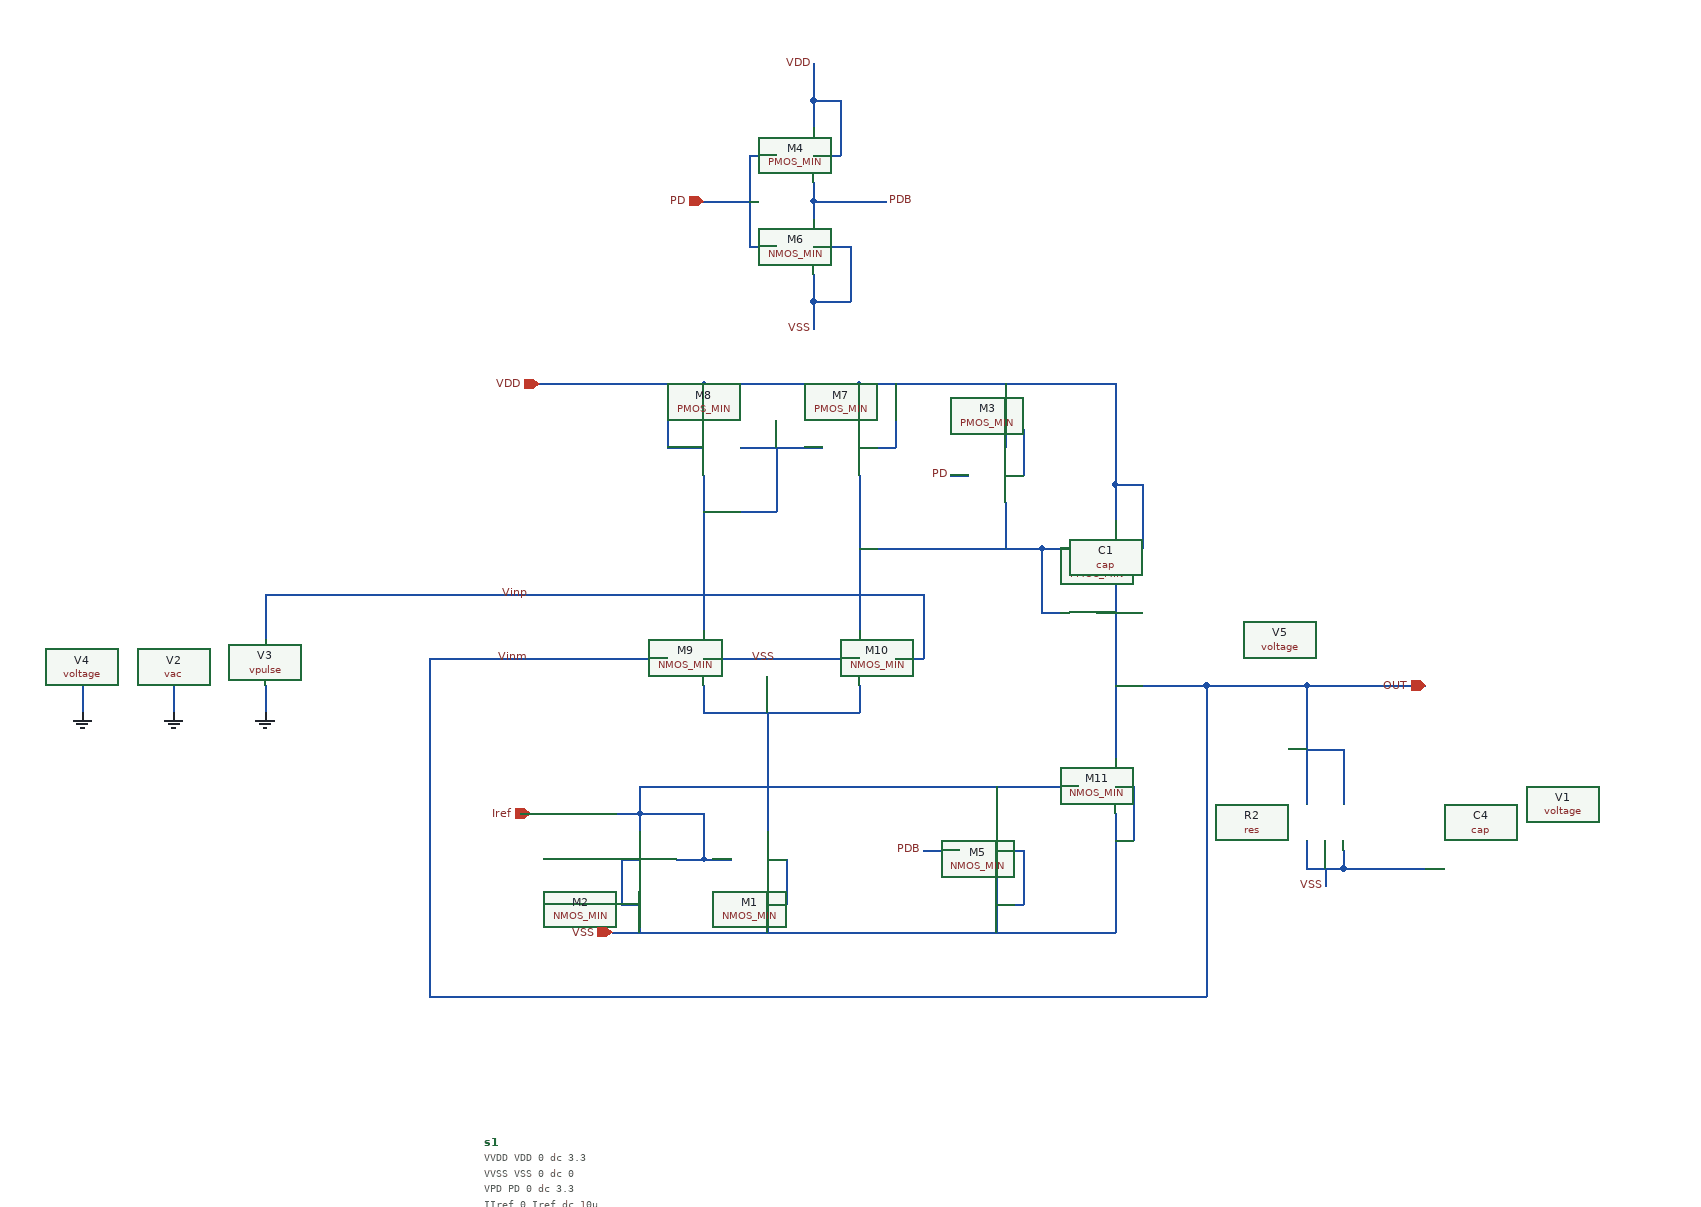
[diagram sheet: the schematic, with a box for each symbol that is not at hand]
v {xschem version=3.4.8RC file_version=1.3}
G {}
K {}
V {}
S {}
F {}
E {}
N 270 160 300 160 {lab=VDD}
N -360 -20 -180 -20 {lab=VDD}
N -180 -20 -180 20 {lab=VDD}
N -180 -20 -10 -20 {lab=VDD}
N -10 -20 -10 20 {lab=VDD}
N -10 -20 170 -20 {lab=VDD}
N 270 -20 270 90 {lab=VDD}
N 300 90 300 160 {lab=VDD}
N 270 90 300 90 {lab=VDD}
N -10 50 30 50 {lab=VDD}
N 30 -20 30 50 {lab=VDD}
N -220 50 -180 50 {lab=VDD}
N -220 -20 -220 50 {lab=VDD}
N -100 50 -100 100 {lab=#net1}
N -180 120 -100 120 {lab=#net1}
N -360 210 60 210 {lab=Vinp}
N 60 210 60 280 {lab=Vinp}
N 30 280 60 280 {lab=Vinp}
N -180 310 -180 340 {lab=#net2}
N -180 340 -10 340 {lab=#net2}
N -10 310 -10 340 {lab=#net2}
N -180 280 -10 280 {lab=VSS}
N -140 50 -50 50 {lab=#net1}
N -60 580 170 580 {lab=VSS}
N -300 280 -220 280 {lab=OUT}
N -320 280 -300 280 {lab=OUT}
N -110 530 -110 580 {lab=VSS}
N -110 500 -90 500 {lab=VSS}
N -90 500 -90 550 {lab=VSS}
N -110 550 -90 550 {lab=VSS}
N -280 580 -60 580 {lab=VSS}
N -180 500 -150 500 {lab=Iref}
N -210 500 -180 500 {lab=Iref}
N -250 530 -250 580 {lab=VSS}
N -270 500 -250 500 {lab=VSS}
N -270 500 -270 550 {lab=VSS}
N -270 550 -250 550 {lab=VSS}
N -10 160 50 160 {lab=#net3}
N -180 450 -180 500 {lab=Iref}
N -250 450 -180 450 {lab=Iref}
N -380 450 -250 450 {lab=Iref}
N -250 450 -250 470 {lab=Iref}
N -250 420 -250 450 {lab=Iref}
N 270 190 270 220 {lab=OUT}
N 230 -20 270 -20 {lab=VDD}
N 190 160 230 160 {lab=#net3}
N 190 160 190 230 {lab=#net3}
N 270 450 270 580 {lab=VSS}
N 230 580 270 580 {lab=VSS}
N 270 420 290 420 {lab=VSS}
N 290 420 290 480 {lab=VSS}
N 270 480 290 480 {lab=VSS}
N -480 650 280 650 {lab=OUT}
N -480 280 -480 650 {lab=OUT}
N -480 280 -320 280 {lab=OUT}
N -110 380 -110 470 {lab=#net2}
N 370 310 370 640 {lab=OUT}
N 250 230 270 230 {lab=OUT}
N 190 230 210 230 {lab=#net3}
N -110 340 -110 360 {lab=#net2}
N 270 220 270 320 {lab=OUT}
N 50 160 80 160 {lab=#net3}
N 270 320 270 340 {lab=OUT}
N 80 160 130 160 {lab=#net3}
N -180 80 -180 250 {lab=#net1}
N -100 100 -100 120 {lab=#net1}
N -10 80 -10 250 {lab=#net3}
N 270 90 270 120 {lab=VDD}
N 270 120 270 130 {lab=VDD}
N -110 360 -110 380 {lab=#net2}
N -660 210 -660 260 {lab=Vinp}
N -660 210 -360 210 {lab=Vinp}
N 140 520 140 560 {lab=VSS}
N 60 490 100 490 {lab=PDB}
N 140 420 140 450 {lab=Iref}
N 140 490 170 490 {lab=VSS}
N 170 490 170 550 {lab=VSS}
N 140 550 170 550 {lab=VSS}
N 140 450 140 460 {lab=Iref}
N 140 560 140 580 {lab=VSS}
N 150 30 150 50 {lab=VDD}
N 150 80 170 80 {lab=VDD}
N 170 30 170 80 {lab=VDD}
N 150 30 170 30 {lab=VDD}
N 150 120 150 160 {lab=#net3}
N 90 80 110 80 {lab=PD}
N 270 340 270 390 {lab=OUT}
N -250 420 80 420 {lab=Iref}
N 130 160 190 160 {lab=#net3}
N 170 -20 230 -20 {lab=VDD}
N 150 110 150 120 {lab=#net3}
N 150 -20 150 30 {lab=VDD}
N 170 580 230 580 {lab=VSS}
N 80 420 230 420 {lab=Iref}
N -60 -330 -60 -300 {lab=VDD}
N -60 -170 -20 -170 {lab=VSS}
N -20 -170 -20 -110 {lab=VSS}
N -60 -110 -20 -110 {lab=VSS}
N -60 -270 -30 -270 {lab=VDD}
N -30 -330 -30 -270 {lab=VDD}
N -60 -330 -30 -330 {lab=VDD}
N -60 -220 -60 -200 {lab=PDB}
N -60 -140 -60 -110 {lab=VSS}
N -60 -340 -60 -330 {lab=VDD}
N -60 -240 -60 -220 {lab=PDB}
N -60 -110 -60 -80 {lab=VSS}
N -130 -270 -100 -270 {lab=PD}
N -130 -270 -130 -170 {lab=PD}
N -130 -170 -100 -170 {lab=PD}
N -60 -350 -60 -340 {lab=VDD}
N -60 -370 -60 -350 {lab=VDD}
N -180 -220 -130 -220 {lab=PD}
N -60 -220 20 -220 {lab=PDB}
N 280 650 370 650 {lab=OUT}
N 370 640 370 650 {lab=OUT}
N -760 310 -760 340 {lab=GND}
N -660 310 -660 340 {lab=GND}
N -860 310 -860 340 {lab=GND}
N 480 310 540 310 {lab=OUT}
N 480 480 480 510 {lab=VSS}
N 500 510 500 530 {lab=VSS}
N 480 400 480 440 {lab=OUT}
N 480 370 480 400 {lab=OUT}
N 480 380 520 380 {lab=OUT}
N 520 380 520 440 {lab=OUT}
N 520 490 520 510 {lab=VSS}
N 480 510 520 510 {lab=VSS}
N 480 310 480 370 {lab=OUT}
N 540 310 610 310 {lab=OUT}
N 520 510 610 510 {lab=VSS}
N 270 310 370 310 {lab=OUT}
N 370 310 390 310 {lab=OUT}
N 470 310 480 310 {lab=OUT}
N 440 310 470 310 {lab=OUT}
N 390 310 440 310 {lab=OUT}
C {PMOS_MIN.sym} -50 50 0 0 {name=M7 model=p3.0 w=20u l=0.5u as=0 ps=0 ad=0 pd=0 m=1}
C {PMOS_MIN.sym} -140 50 0 1 {name=M8 model=p3.0 w=20u l=0.5u as=0 ps=0 ad=0 pd=0 m=1}
C {NMOS_MIN.sym} -220 280 0 0 {name=M9 model=n3.0 w=20u l=0.5u as=0 ps=0 ad=0 pd=0 m=1}
C {NMOS_MIN.sym} 30 280 0 1 {name=M10 model=n3.0 w=20u l=0.5u as=0 ps=0 ad=0 pd=0 m=1}
C {NMOS_MIN.sym} 230 420 0 0 {name=M11 model=n3.0 w=20u l=0.5u as=0 ps=0 ad=0 pd=0 m=1}
C {PMOS_MIN.sym} 230 160 0 0 {name=M12 model=p3.0 w=40u l=0.5u as=0 ps=0 ad=0 pd=0 m=1}
C {ipin.sym} -360 -20 0 0 {name=p5 lab=VDD}
C {iopin.sym} 610 310 0 0 {name=p7 lab=OUT}
C {ipin.sym} -370 450 0 0 {name=p1 lab=Iref}
C {NMOS_MIN.sym} -150 500 0 0 {name=M1 model=n3.0 w=20u l=0.5u as=0 ps=0 ad=0 pd=0 m=1}
C {NMOS_MIN.sym} -210 500 0 1 {name=M2 model=n3.0 w=20u l=0.5u as=0 ps=0 ad=0 pd=0 m=1}
C {lab_pin.sym} -370 210 1 0 {name=l3 sig_type=std_logic lab=Vinp}
C {lab_pin.sym} -100 280 1 0 {name=l5 sig_type=std_logic lab=VSS}
C {ipin.sym} -280 580 0 0 {name=p2 lab=VSS}
C {cap.sym} 250 220 1 0 {name=C1
m=1
value=1p
footprint=1206
device=ceramic}
C {lab_pin.sym} -370 280 3 0 {name=l8 sig_type=std_logic lab=Vinm}
C {NMOS_MIN.sym} 100 490 0 0 {name=M5 model=n3.0 w=3.5u l=0.35u as=0 ps=0 ad=0 pd=0 m=1}
C {PMOS_MIN.sym} 110 80 0 0 {name=M3 model=p3.0 w=3.5u l=0.35u as=0 ps=0 ad=0 pd=0 m=1}
C {PMOS_MIN.sym} -100 -270 0 0 {name=M4 model=p3.0 w=3.5u l=0.35u as=0 ps=0 ad=0 pd=0 m=1}
C {NMOS_MIN.sym} -100 -170 0 0 {name=M6 model=n3.0 w=3.5u l=0.35u as=0 ps=0 ad=0 pd=0 m=1}
C {lab_pin.sym} -60 -370 1 0 {name=l1 sig_type=std_logic lab=VDD}
C {lab_pin.sym} -60 -80 3 0 {name=l4 sig_type=std_logic lab=VSS}
C {ipin.sym} -180 -220 0 0 {name=p4 lab=PD}
C {lab_pin.sym} 20 -220 2 0 {name=l6 sig_type=std_logic lab=PDB}
C {lab_pin.sym} 60 490 0 0 {name=l7 sig_type=std_logic lab=PDB}
C {lab_pin.sym} 90 80 0 0 {name=l9 sig_type=std_logic lab=PD}
C {gnd.sym} -760 340 0 0 {name=l15 lab=GND}
C {vac.sym} -760 250 0 0 {name=V2 value="1.65 ac 1"}
C {vpulse.sym} -660 250 0 0 {name=V3 value="pulse(0 3.3 100n 1n 1n 3u 6u)"}
C {gnd.sym} -660 340 0 0 {name=l10 lab=GND}
C {voltage.sym} -860 250 0 0 {name=V4 value=0}
C {gnd.sym} -860 340 0 0 {name=l11 lab=GND}
C {res.sym} 510 430 0 0 {name=R2
value=1meg
footprint=1206
device=resistor
m=1}
C {lab_pin.sym} 500 530 3 0 {name=l14 sig_type=std_logic lab=VSS}
C {cap.sym} 490 480 2 0 {name=C4
m=1
value=1p
footprint=1206
device=ceramic}
C {code_shown.sym} -420 810 0 0 {name=s1 only_toplevel=false value=
"
VVDD VDD 0 dc 3.3
VVSS VSS 0 dc 0
VPD PD 0 dc 3.3
IIref 0 Iref dc 10u

*VVIN+ VIN+ 0 pulse(0 3.3 100n 1n 1n 200n 400n)
*VVIN+ VIN+ 0 dc 0

.probe <alli>
.meas DC IOUT AVG I(V5)
*.meas TRAN VusH TRIG V(OUT) VAL=0.3281 RISE=1 TARG V(OUT) VAL=2.9529 RISE=1
*.meas TRAN VusL TRIG V(OUT) VAL=2.9529 FALL=1 TARG V(OUT) VAL=0.3281 FALL=1
*.meas TRAN OUTMAX MAX V(OUT) from=0 to=3u

.include /home/raidonn/LRCircuit/spicemodel/ocs65_stl_n3_typ.para
.include /home/raidonn/LRCircuit/spicemodel/ocs65_stl_p3_typ.para

.control
save all
*dc V3 0 3.3 0.01
*dc V1 0 3.3 0.01
*ac dec 10 1k 1g
tran 1n 6u
plot V(Vinp) V(OUT)
*plot I(V5)
*plot db(OUT/(OUT-Vinp)) ph(OUT/(OUT-Vinp))*180/3.14

write "Opamp_ACsim_ver2.raw"

.endc"
}
C {voltage.sym} 760 440 0 0 {name=V1 value=3.3}
C {voltage.sym} 450 260 1 0 {name=V5 value=0}
